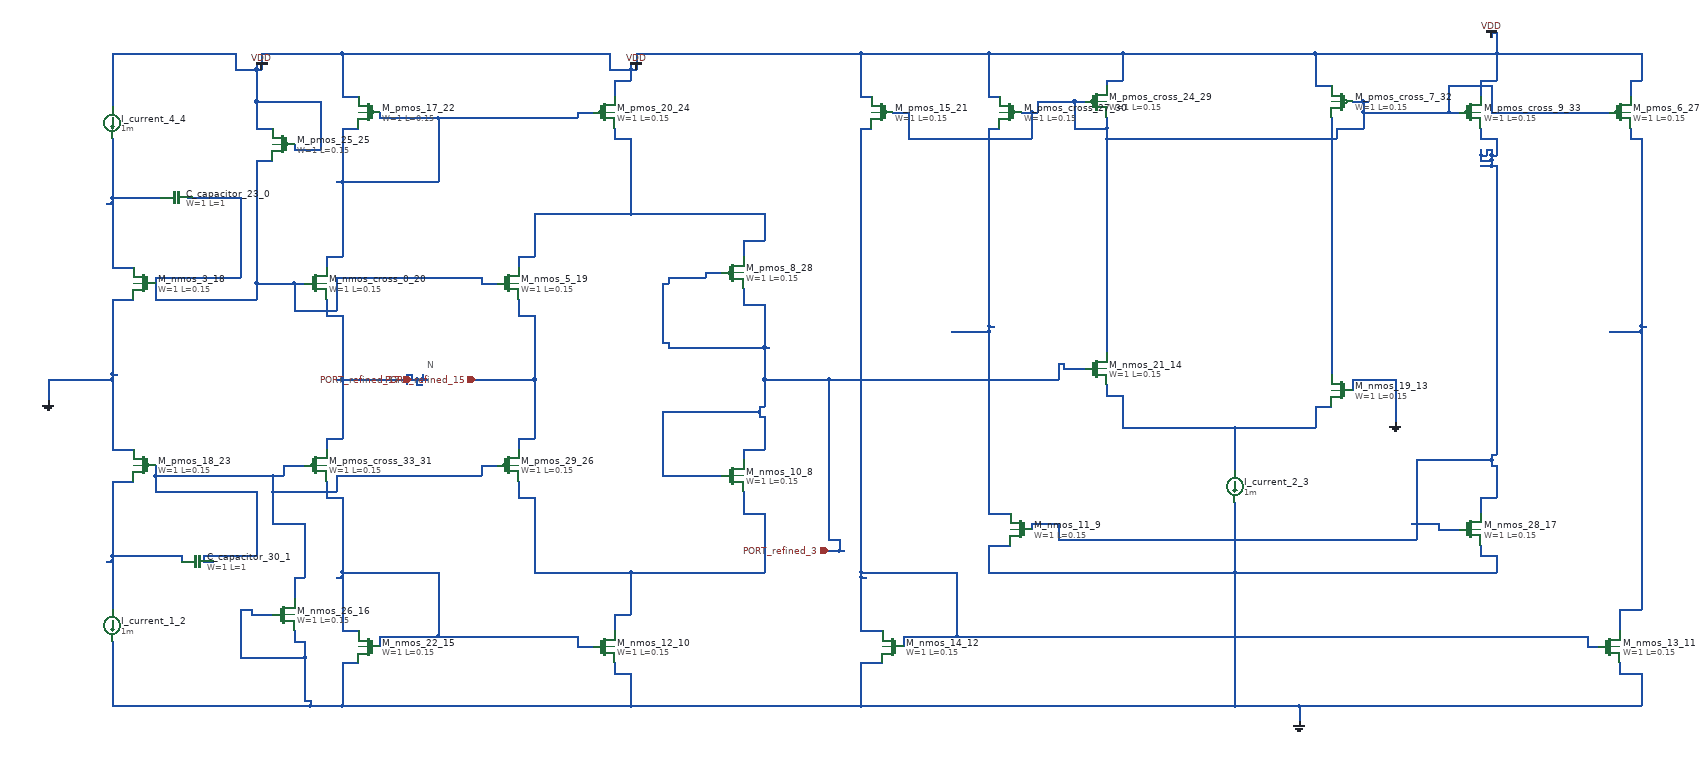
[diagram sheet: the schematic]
v {xschem version=3.4.8 file_version=1.2}
G {}
K {}
V {}
S {}
E {}
C {sky130_fd_pr/cap_mim_m3_1.sym} 320 440 1 0 {name="C_capacitor_23_0" model=cap_mim_m3_1 W=1 L=1 MF=1 spiceprefix=X}
C {sky130_fd_pr/cap_mim_m3_1.sym} 360 1120 1 0 {name="C_capacitor_30_1" model=cap_mim_m3_1 W=1 L=1 MF=1 spiceprefix=X}
C {devices/isource.sym} 200 1240 0 0 {name="I_current_1_2" value=1m}
C {devices/isource.sym} 2300 980 0 0 {name="I_current_2_3" value=1m}
C {devices/isource.sym} 200 300 0 0 {name="I_current_4_4" value=1m}
C {devices/gnd.sym} 2600 860 0 0 {name="l_gnd_16_5" lab="GND"}
C {devices/gnd.sym} 80 820 0 0 {name="l_gnd_31_6" lab="GND"}
C {devices/gnd.sym} 2420 1420 0 0 {name="l_gnd_37_7" lab="GND"}
C {sky130_fd_pr/nfet3_01v8.sym} 1360 960 0 0 {name="M_nmos_10_8"
W=1
L=0.15
body=GND
nf=1
mult=1
ad="expr('int((@nf + 1)/2) * @W / @nf * 0.29')"
pd="expr('2*int((@nf + 1)/2) * (@W / @nf + 0.29)')"
as="expr('int((@nf + 2)/2) * @W / @nf * 0.29')"
ps="expr('2*int((@nf + 2)/2) * (@W / @nf + 0.29)')"
nrd="expr('0.29 / @W ')" nrs="expr('0.29 / @W ')"
sa=0 sb=0 sd=0
model=nfet_01v8
spiceprefix=X
}
C {sky130_fd_pr/nfet3_01v8.sym} 1900 1060 0 1 {name="M_nmos_11_9"
W=1
L=0.15
body=GND
nf=1
mult=1
ad="expr('int((@nf + 1)/2) * @W / @nf * 0.29')"
pd="expr('2*int((@nf + 1)/2) * (@W / @nf + 0.29)')"
as="expr('int((@nf + 2)/2) * @W / @nf * 0.29')"
ps="expr('2*int((@nf + 2)/2) * (@W / @nf + 0.29)')"
nrd="expr('0.29 / @W ')" nrs="expr('0.29 / @W ')"
sa=0 sb=0 sd=0
model=nfet_01v8
spiceprefix=X
}
C {sky130_fd_pr/nfet3_01v8.sym} 1120 1280 0 0 {name="M_nmos_12_10"
W=1
L=0.15
body=GND
nf=1
mult=1
ad="expr('int((@nf + 1)/2) * @W / @nf * 0.29')"
pd="expr('2*int((@nf + 1)/2) * (@W / @nf + 0.29)')"
as="expr('int((@nf + 2)/2) * @W / @nf * 0.29')"
ps="expr('2*int((@nf + 2)/2) * (@W / @nf + 0.29)')"
nrd="expr('0.29 / @W ')" nrs="expr('0.29 / @W ')"
sa=0 sb=0 sd=0
model=nfet_01v8
spiceprefix=X
}
C {sky130_fd_pr/nfet3_01v8.sym} 3000 1280 0 0 {name="M_nmos_13_11"
W=1
L=0.15
body=GND
nf=1
mult=1
ad="expr('int((@nf + 1)/2) * @W / @nf * 0.29')"
pd="expr('2*int((@nf + 1)/2) * (@W / @nf + 0.29)')"
as="expr('int((@nf + 2)/2) * @W / @nf * 0.29')"
ps="expr('2*int((@nf + 2)/2) * (@W / @nf + 0.29)')"
nrd="expr('0.29 / @W ')" nrs="expr('0.29 / @W ')"
sa=0 sb=0 sd=0
model=nfet_01v8
spiceprefix=X
}
C {sky130_fd_pr/nfet3_01v8.sym} 1660 1280 0 1 {name="M_nmos_14_12"
W=1
L=0.15
body=GND
nf=1
mult=1
ad="expr('int((@nf + 1)/2) * @W / @nf * 0.29')"
pd="expr('2*int((@nf + 1)/2) * (@W / @nf + 0.29)')"
as="expr('int((@nf + 2)/2) * @W / @nf * 0.29')"
ps="expr('2*int((@nf + 2)/2) * (@W / @nf + 0.29)')"
nrd="expr('0.29 / @W ')" nrs="expr('0.29 / @W ')"
sa=0 sb=0 sd=0
model=nfet_01v8
spiceprefix=X
}
C {sky130_fd_pr/nfet3_01v8.sym} 2500 800 0 1 {name="M_nmos_19_13"
W=1
L=0.15
body=GND
nf=1
mult=1
ad="expr('int((@nf + 1)/2) * @W / @nf * 0.29')"
pd="expr('2*int((@nf + 1)/2) * (@W / @nf + 0.29)')"
as="expr('int((@nf + 2)/2) * @W / @nf * 0.29')"
ps="expr('2*int((@nf + 2)/2) * (@W / @nf + 0.29)')"
nrd="expr('0.29 / @W ')" nrs="expr('0.29 / @W ')"
sa=0 sb=0 sd=0
model=nfet_01v8
spiceprefix=X
}
C {sky130_fd_pr/nfet3_01v8.sym} 2040 760 0 0 {name="M_nmos_21_14"
W=1
L=0.15
body=GND
nf=1
mult=1
ad="expr('int((@nf + 1)/2) * @W / @nf * 0.29')"
pd="expr('2*int((@nf + 1)/2) * (@W / @nf + 0.29)')"
as="expr('int((@nf + 2)/2) * @W / @nf * 0.29')"
ps="expr('2*int((@nf + 2)/2) * (@W / @nf + 0.29)')"
nrd="expr('0.29 / @W ')" nrs="expr('0.29 / @W ')"
sa=0 sb=0 sd=0
model=nfet_01v8
spiceprefix=X
}
C {sky130_fd_pr/nfet3_01v8.sym} 680 1280 0 1 {name="M_nmos_22_15"
W=1
L=0.15
body=GND
nf=1
mult=1
ad="expr('int((@nf + 1)/2) * @W / @nf * 0.29')"
pd="expr('2*int((@nf + 1)/2) * (@W / @nf + 0.29)')"
as="expr('int((@nf + 2)/2) * @W / @nf * 0.29')"
ps="expr('2*int((@nf + 2)/2) * (@W / @nf + 0.29)')"
nrd="expr('0.29 / @W ')" nrs="expr('0.29 / @W ')"
sa=0 sb=0 sd=0
model=nfet_01v8
spiceprefix=X
}
C {sky130_fd_pr/nfet3_01v8.sym} 520 1220 0 0 {name="M_nmos_26_16"
W=1
L=0.15
body=GND
nf=1
mult=1
ad="expr('int((@nf + 1)/2) * @W / @nf * 0.29')"
pd="expr('2*int((@nf + 1)/2) * (@W / @nf + 0.29)')"
as="expr('int((@nf + 2)/2) * @W / @nf * 0.29')"
ps="expr('2*int((@nf + 2)/2) * (@W / @nf + 0.29)')"
nrd="expr('0.29 / @W ')" nrs="expr('0.29 / @W ')"
sa=0 sb=0 sd=0
model=nfet_01v8
spiceprefix=X
}
C {sky130_fd_pr/nfet3_01v8.sym} 2740 1060 0 0 {name="M_nmos_28_17"
W=1
L=0.15
body=GND
nf=1
mult=1
ad="expr('int((@nf + 1)/2) * @W / @nf * 0.29')"
pd="expr('2*int((@nf + 1)/2) * (@W / @nf + 0.29)')"
as="expr('int((@nf + 2)/2) * @W / @nf * 0.29')"
ps="expr('2*int((@nf + 2)/2) * (@W / @nf + 0.29)')"
nrd="expr('0.29 / @W ')" nrs="expr('0.29 / @W ')"
sa=0 sb=0 sd=0
model=nfet_01v8
spiceprefix=X
}
C {sky130_fd_pr/nfet3_01v8.sym} 260 600 0 1 {name="M_nmos_3_18"
W=1
L=0.15
body=GND
nf=1
mult=1
ad="expr('int((@nf + 1)/2) * @W / @nf * 0.29')"
pd="expr('2*int((@nf + 1)/2) * (@W / @nf + 0.29)')"
as="expr('int((@nf + 2)/2) * @W / @nf * 0.29')"
ps="expr('2*int((@nf + 2)/2) * (@W / @nf + 0.29)')"
nrd="expr('0.29 / @W ')" nrs="expr('0.29 / @W ')"
sa=0 sb=0 sd=0
model=nfet_01v8
spiceprefix=X
}
C {sky130_fd_pr/nfet3_01v8.sym} 940 600 0 0 {name="M_nmos_5_19"
W=1
L=0.15
body=GND
nf=1
mult=1
ad="expr('int((@nf + 1)/2) * @W / @nf * 0.29')"
pd="expr('2*int((@nf + 1)/2) * (@W / @nf + 0.29)')"
as="expr('int((@nf + 2)/2) * @W / @nf * 0.29')"
ps="expr('2*int((@nf + 2)/2) * (@W / @nf + 0.29)')"
nrd="expr('0.29 / @W ')" nrs="expr('0.29 / @W ')"
sa=0 sb=0 sd=0
model=nfet_01v8
spiceprefix=X
}
C {sky130_fd_pr/nfet3_01v8.sym} 580 600 0 0 {name="M_nmos_cross_0_20"
W=1
L=0.15
body=GND
nf=1
mult=1
ad="expr('int((@nf + 1)/2) * @W / @nf * 0.29')"
pd="expr('2*int((@nf + 1)/2) * (@W / @nf + 0.29)')"
as="expr('int((@nf + 2)/2) * @W / @nf * 0.29')"
ps="expr('2*int((@nf + 2)/2) * (@W / @nf + 0.29)')"
nrd="expr('0.29 / @W ')" nrs="expr('0.29 / @W ')"
sa=0 sb=0 sd=0
model=nfet_01v8
spiceprefix=X
}
C {sky130_fd_pr/pfet3_01v8.sym} 1640 280 0 1 {name="M_pmos_15_21"
W=1
L=0.15
body=VDD
nf=1
mult=1
ad="expr('int((@nf + 1)/2) * @W / @nf * 0.29')"
pd="expr('2*int((@nf + 1)/2) * (@W / @nf + 0.29)')"
as="expr('int((@nf + 2)/2) * @W / @nf * 0.29')"
ps="expr('2*int((@nf + 2)/2) * (@W / @nf + 0.29)')"
nrd="expr('0.29 / @W ')" nrs="expr('0.29 / @W ')"
sa=0 sb=0 sd=0
model=pfet_01v8
spiceprefix=X
}
C {sky130_fd_pr/pfet3_01v8.sym} 680 280 0 1 {name="M_pmos_17_22"
W=1
L=0.15
body=VDD
nf=1
mult=1
ad="expr('int((@nf + 1)/2) * @W / @nf * 0.29')"
pd="expr('2*int((@nf + 1)/2) * (@W / @nf + 0.29)')"
as="expr('int((@nf + 2)/2) * @W / @nf * 0.29')"
ps="expr('2*int((@nf + 2)/2) * (@W / @nf + 0.29)')"
nrd="expr('0.29 / @W ')" nrs="expr('0.29 / @W ')"
sa=0 sb=0 sd=0
model=pfet_01v8
spiceprefix=X
}
C {sky130_fd_pr/pfet3_01v8.sym} 260 940 0 1 {name="M_pmos_18_23"
W=1
L=0.15
body=VDD
nf=1
mult=1
ad="expr('int((@nf + 1)/2) * @W / @nf * 0.29')"
pd="expr('2*int((@nf + 1)/2) * (@W / @nf + 0.29)')"
as="expr('int((@nf + 2)/2) * @W / @nf * 0.29')"
ps="expr('2*int((@nf + 2)/2) * (@W / @nf + 0.29)')"
nrd="expr('0.29 / @W ')" nrs="expr('0.29 / @W ')"
sa=0 sb=0 sd=0
model=pfet_01v8
spiceprefix=X
}
C {sky130_fd_pr/pfet3_01v8.sym} 1120 280 0 0 {name="M_pmos_20_24"
W=1
L=0.15
body=VDD
nf=1
mult=1
ad="expr('int((@nf + 1)/2) * @W / @nf * 0.29')"
pd="expr('2*int((@nf + 1)/2) * (@W / @nf + 0.29)')"
as="expr('int((@nf + 2)/2) * @W / @nf * 0.29')"
ps="expr('2*int((@nf + 2)/2) * (@W / @nf + 0.29)')"
nrd="expr('0.29 / @W ')" nrs="expr('0.29 / @W ')"
sa=0 sb=0 sd=0
model=pfet_01v8
spiceprefix=X
}
C {sky130_fd_pr/pfet3_01v8.sym} 520 340 0 1 {name="M_pmos_25_25"
W=1
L=0.15
body=VDD
nf=1
mult=1
ad="expr('int((@nf + 1)/2) * @W / @nf * 0.29')"
pd="expr('2*int((@nf + 1)/2) * (@W / @nf + 0.29)')"
as="expr('int((@nf + 2)/2) * @W / @nf * 0.29')"
ps="expr('2*int((@nf + 2)/2) * (@W / @nf + 0.29)')"
nrd="expr('0.29 / @W ')" nrs="expr('0.29 / @W ')"
sa=0 sb=0 sd=0
model=pfet_01v8
spiceprefix=X
}
C {sky130_fd_pr/pfet3_01v8.sym} 940 940 0 0 {name="M_pmos_29_26"
W=1
L=0.15
body=VDD
nf=1
mult=1
ad="expr('int((@nf + 1)/2) * @W / @nf * 0.29')"
pd="expr('2*int((@nf + 1)/2) * (@W / @nf + 0.29)')"
as="expr('int((@nf + 2)/2) * @W / @nf * 0.29')"
ps="expr('2*int((@nf + 2)/2) * (@W / @nf + 0.29)')"
nrd="expr('0.29 / @W ')" nrs="expr('0.29 / @W ')"
sa=0 sb=0 sd=0
model=pfet_01v8
spiceprefix=X
}
C {sky130_fd_pr/pfet3_01v8.sym} 3020 280 0 0 {name="M_pmos_6_27"
W=1
L=0.15
body=VDD
nf=1
mult=1
ad="expr('int((@nf + 1)/2) * @W / @nf * 0.29')"
pd="expr('2*int((@nf + 1)/2) * (@W / @nf + 0.29)')"
as="expr('int((@nf + 2)/2) * @W / @nf * 0.29')"
ps="expr('2*int((@nf + 2)/2) * (@W / @nf + 0.29)')"
nrd="expr('0.29 / @W ')" nrs="expr('0.29 / @W ')"
sa=0 sb=0 sd=0
model=pfet_01v8
spiceprefix=X
}
C {sky130_fd_pr/pfet3_01v8.sym} 1360 580 0 0 {name="M_pmos_8_28"
W=1
L=0.15
body=VDD
nf=1
mult=1
ad="expr('int((@nf + 1)/2) * @W / @nf * 0.29')"
pd="expr('2*int((@nf + 1)/2) * (@W / @nf + 0.29)')"
as="expr('int((@nf + 2)/2) * @W / @nf * 0.29')"
ps="expr('2*int((@nf + 2)/2) * (@W / @nf + 0.29)')"
nrd="expr('0.29 / @W ')" nrs="expr('0.29 / @W ')"
sa=0 sb=0 sd=0
model=pfet_01v8
spiceprefix=X
}
C {sky130_fd_pr/pfet3_01v8.sym} 2040 260 0 0 {name="M_pmos_cross_24_29"
W=1
L=0.15
body=VDD
nf=1
mult=1
ad="expr('int((@nf + 1)/2) * @W / @nf * 0.29')"
pd="expr('2*int((@nf + 1)/2) * (@W / @nf + 0.29)')"
as="expr('int((@nf + 2)/2) * @W / @nf * 0.29')"
ps="expr('2*int((@nf + 2)/2) * (@W / @nf + 0.29)')"
nrd="expr('0.29 / @W ')" nrs="expr('0.29 / @W ')"
sa=0 sb=0 sd=0
model=pfet_01v8
spiceprefix=X
}
C {sky130_fd_pr/pfet3_01v8.sym} 1880 280 0 1 {name="M_pmos_cross_27_30"
W=1
L=0.15
body=VDD
nf=1
mult=1
ad="expr('int((@nf + 1)/2) * @W / @nf * 0.29')"
pd="expr('2*int((@nf + 1)/2) * (@W / @nf + 0.29)')"
as="expr('int((@nf + 2)/2) * @W / @nf * 0.29')"
ps="expr('2*int((@nf + 2)/2) * (@W / @nf + 0.29)')"
nrd="expr('0.29 / @W ')" nrs="expr('0.29 / @W ')"
sa=0 sb=0 sd=0
model=pfet_01v8
spiceprefix=X
}
C {sky130_fd_pr/pfet3_01v8.sym} 580 940 0 0 {name="M_pmos_cross_33_31"
W=1
L=0.15
body=VDD
nf=1
mult=1
ad="expr('int((@nf + 1)/2) * @W / @nf * 0.29')"
pd="expr('2*int((@nf + 1)/2) * (@W / @nf + 0.29)')"
as="expr('int((@nf + 2)/2) * @W / @nf * 0.29')"
ps="expr('2*int((@nf + 2)/2) * (@W / @nf + 0.29)')"
nrd="expr('0.29 / @W ')" nrs="expr('0.29 / @W ')"
sa=0 sb=0 sd=0
model=pfet_01v8
spiceprefix=X
}
C {sky130_fd_pr/pfet3_01v8.sym} 2500 260 0 1 {name="M_pmos_cross_7_32"
W=1
L=0.15
body=VDD
nf=1
mult=1
ad="expr('int((@nf + 1)/2) * @W / @nf * 0.29')"
pd="expr('2*int((@nf + 1)/2) * (@W / @nf + 0.29)')"
as="expr('int((@nf + 2)/2) * @W / @nf * 0.29')"
ps="expr('2*int((@nf + 2)/2) * (@W / @nf + 0.29)')"
nrd="expr('0.29 / @W ')" nrs="expr('0.29 / @W ')"
sa=0 sb=0 sd=0
model=pfet_01v8
spiceprefix=X
}
C {sky130_fd_pr/pfet3_01v8.sym} 2740 280 0 0 {name="M_pmos_cross_9_33"
W=1
L=0.15
body=VDD
nf=1
mult=1
ad="expr('int((@nf + 1)/2) * @W / @nf * 0.29')"
pd="expr('2*int((@nf + 1)/2) * (@W / @nf + 0.29)')"
as="expr('int((@nf + 2)/2) * @W / @nf * 0.29')"
ps="expr('2*int((@nf + 2)/2) * (@W / @nf + 0.29)')"
nrd="expr('0.29 / @W ')" nrs="expr('0.29 / @W ')"
sa=0 sb=0 sd=0
model=pfet_01v8
spiceprefix=X
}
C {devices/ipin.sym} 880 780 0 0 {name="p_port_35_34" lab="PORT_refined_15"}
C {devices/ipin.sym} 760 780 0 0 {name="p_port_38_35" lab="PORT_refined_17"}
T {N} 790 740 0 0 0.25 0.25 {}
C {devices/ipin.sym} 1540 1100 0 0 {name="p_port_99_36" lab="PORT_refined_3"}
C {devices/vdd.sym} 2780 140 0 0 {name="l_vdd_32_37" lab="VDD"}
C {devices/vdd.sym} 480 200 0 0 {name="l_vdd_34_38" lab="VDD"}
C {devices/vdd.sym} 1180 200 0 0 {name="l_vdd_36_39" lab="VDD"}
N 200 570 240 570 {}
N 190 450 200 450 {}
N 200 440 290 440 {}
N 290 440 300 440 {}
N 200 570 200 450 {}
N 200 450 200 440 {}
N 200 440 200 330 {}
N 540 650 620 650 {}
N 280 630 470 630 {}
N 470 600 540 600 {}
N 540 600 560 600 {}
N 890 600 920 600 {}
N 280 590 440 590 {}
N 620 590 890 590 {}
N 340 440 350 440 {}
N 350 440 440 440 {}
N 470 370 500 370 {}
N 280 630 280 600 {}
N 280 600 280 590 {}
N 440 590 440 440 {}
N 470 630 470 600 {}
N 470 600 470 370 {}
N 540 650 540 600 {}
N 620 650 620 590 {}
N 890 600 890 590 {}
N 2960 1280 2980 1280 {}
N 1680 1260 1780 1260 {}
N 1780 1260 2960 1260 {}
N 1600 1250 1640 1250 {}
N 1600 1150 1610 1150 {}
N 1600 1140 1780 1140 {}
N 1600 310 1620 310 {}
N 1600 1250 1600 1150 {}
N 1600 1150 1600 1140 {}
N 1600 1140 1600 310 {}
N 1680 1280 1680 1260 {}
N 1780 1260 1780 1140 {}
N 2960 1280 2960 1260 {}
N 2090 870 2300 870 {}
N 2300 870 2450 870 {}
N 2450 830 2480 830 {}
N 2060 810 2090 810 {}
N 2060 810 2060 790 {}
N 2090 870 2090 810 {}
N 2300 950 2300 870 {}
N 2450 870 2450 830 {}
N 1690 330 1920 330 {}
N 2060 330 2490 330 {}
N 2000 310 2060 310 {}
N 2490 310 2540 310 {}
N 1660 280 1690 280 {}
N 1900 280 1920 280 {}
N 1920 280 1930 280 {}
N 2540 280 2700 280 {}
N 2700 280 2720 280 {}
N 2780 280 3000 280 {}
N 1930 260 2000 260 {}
N 2000 260 2020 260 {}
N 2520 260 2540 260 {}
N 2540 260 2550 260 {}
N 2700 230 2780 230 {}
N 1690 330 1690 280 {}
N 1920 330 1920 280 {}
N 1930 280 1930 260 {}
N 2000 310 2000 260 {}
N 2060 730 2060 330 {}
N 2060 330 2060 310 {}
N 2060 310 2060 290 {}
N 2490 330 2490 310 {}
N 2540 310 2540 280 {}
N 2540 280 2540 260 {}
N 2700 280 2700 230 {}
N 2780 280 2780 230 {}
N 540 1150 560 1150 {}
N 370 1120 390 1120 {}
N 370 1110 470 1110 {}
N 500 1050 560 1050 {}
N 280 990 470 990 {}
N 500 990 620 990 {}
N 280 960 500 960 {}
N 500 960 520 960 {}
N 620 960 890 960 {}
N 520 940 560 940 {}
N 890 940 920 940 {}
N 280 990 280 960 {}
N 280 960 280 940 {}
N 370 1120 370 1110 {}
N 470 1110 470 990 {}
N 500 1050 500 990 {}
N 500 990 500 960 {}
N 520 960 520 940 {}
N 540 1190 540 1150 {}
N 560 1150 560 1050 {}
N 620 990 620 960 {}
N 890 960 890 940 {}
N 960 550 990 550 {}
N 1380 520 1420 520 {}
N 990 470 1170 470 {}
N 1170 470 1420 470 {}
N 1140 330 1170 330 {}
N 960 570 960 550 {}
N 990 550 990 470 {}
N 1140 330 1140 310 {}
N 1170 470 1170 330 {}
N 1380 550 1380 520 {}
N 1420 520 1420 470 {}
N 960 890 990 890 {}
N 870 780 880 780 {}
N 880 780 990 780 {}
N 960 660 990 660 {}
N 960 910 960 890 {}
N 960 660 960 630 {}
N 990 890 990 780 {}
N 990 780 990 660 {}
N 600 550 630 550 {}
N 620 410 630 410 {}
N 630 410 810 410 {}
N 630 310 660 310 {}
N 700 290 810 290 {}
N 810 290 1070 290 {}
N 1070 280 1100 280 {}
N 600 570 600 550 {}
N 630 550 630 410 {}
N 630 410 630 310 {}
N 700 290 700 280 {}
N 810 410 810 290 {}
N 1070 290 1070 280 {}
N 600 890 630 890 {}
N 770 790 780 790 {}
N 620 780 630 780 {}
N 630 780 750 780 {}
N 760 780 770 780 {}
N 770 780 780 780 {}
N 780 780 790 780 {}
N 750 770 760 770 {}
N 600 660 630 660 {}
N 600 910 600 890 {}
N 600 660 600 630 {}
N 630 890 630 780 {}
N 630 780 630 660 {}
N 750 790 750 780 {}
N 750 780 750 770 {}
N 760 780 760 770 {}
N 770 790 770 780 {}
N 780 780 780 770 {}
N 540 350 590 350 {}
N 470 310 500 310 {}
N 470 260 590 260 {}
N 630 250 660 250 {}
N 1600 250 1620 250 {}
N 1840 250 1860 250 {}
N 2450 230 2480 230 {}
N 1140 220 1170 220 {}
N 2060 220 2090 220 {}
N 2760 220 2790 220 {}
N 3040 220 3060 220 {}
N 430 200 470 200 {}
N 470 200 480 200 {}
N 1130 200 1170 200 {}
N 1170 200 1180 200 {}
N 200 170 430 170 {}
N 480 170 630 170 {}
N 630 170 1130 170 {}
N 1180 170 1600 170 {}
N 1600 170 1840 170 {}
N 1840 170 2090 170 {}
N 2090 170 2450 170 {}
N 2450 170 2790 170 {}
N 2790 170 3060 170 {}
N 2780 130 2790 130 {}
N 200 270 200 170 {}
N 430 200 430 170 {}
N 470 310 470 260 {}
N 470 260 470 200 {}
N 470 200 470 190 {}
N 480 200 480 170 {}
N 540 350 540 340 {}
N 590 350 590 260 {}
N 630 250 630 170 {}
N 1130 200 1130 170 {}
N 1140 250 1140 220 {}
N 1170 220 1170 200 {}
N 1170 200 1170 190 {}
N 1180 200 1180 170 {}
N 1600 250 1600 170 {}
N 1840 250 1840 170 {}
N 2060 230 2060 220 {}
N 2090 220 2090 170 {}
N 2450 230 2450 170 {}
N 2760 250 2760 220 {}
N 2780 140 2780 130 {}
N 2790 220 2790 170 {}
N 2790 170 2790 130 {}
N 3040 250 3040 220 {}
N 3060 220 3060 170 {}
N 2480 770 2480 290 {}
N 200 1390 570 1390 {}
N 570 1390 630 1390 {}
N 630 1390 1170 1390 {}
N 1170 1390 1600 1390 {}
N 1600 1390 2300 1390 {}
N 2300 1390 2420 1390 {}
N 2420 1390 3060 1390 {}
N 560 1380 570 1380 {}
N 1140 1330 1170 1330 {}
N 3020 1330 3060 1330 {}
N 630 1310 660 1310 {}
N 1600 1310 1640 1310 {}
N 440 1300 560 1300 {}
N 540 1270 560 1270 {}
N 460 1220 500 1220 {}
N 440 1210 460 1210 {}
N 1840 1140 2300 1140 {}
N 2300 1140 2790 1140 {}
N 2760 1110 2790 1110 {}
N 1840 1090 1880 1090 {}
N 200 910 240 910 {}
N 80 780 200 780 {}
N 2520 780 2600 780 {}
N 200 770 210 770 {}
N 200 630 240 630 {}
N 80 820 80 780 {}
N 200 1390 200 1270 {}
N 200 910 200 780 {}
N 200 780 200 770 {}
N 200 770 200 630 {}
N 440 1300 440 1210 {}
N 460 1220 460 1210 {}
N 540 1270 540 1250 {}
N 560 1380 560 1300 {}
N 560 1300 560 1270 {}
N 570 1390 570 1380 {}
N 630 1390 630 1310 {}
N 1140 1330 1140 1310 {}
N 1170 1390 1170 1330 {}
N 1600 1390 1600 1310 {}
N 1840 1140 1840 1090 {}
N 2300 1390 2300 1140 {}
N 2300 1140 2300 1010 {}
N 2420 1420 2420 1390 {}
N 2520 800 2520 780 {}
N 2600 860 2600 780 {}
N 2760 1110 2760 1090 {}
N 2790 1140 2790 1110 {}
N 3020 1330 3020 1310 {}
N 3060 1390 3060 1330 {}
N 1540 1100 1560 1100 {}
N 1560 1100 1570 1100 {}
N 1540 1080 1560 1080 {}
N 1230 960 1340 960 {}
N 1380 910 1420 910 {}
N 1410 850 1420 850 {}
N 1230 840 1410 840 {}
N 1410 830 1420 830 {}
N 1420 780 1540 780 {}
N 1540 780 1970 780 {}
N 1980 760 2020 760 {}
N 1970 750 1980 750 {}
N 1240 720 1420 720 {}
N 1420 720 1430 720 {}
N 1230 710 1240 710 {}
N 1380 640 1420 640 {}
N 1230 600 1240 600 {}
N 1240 590 1310 590 {}
N 1310 580 1340 580 {}
N 1230 960 1230 840 {}
N 1230 710 1230 600 {}
N 1240 720 1240 710 {}
N 1240 600 1240 590 {}
N 1310 590 1310 580 {}
N 1380 930 1380 910 {}
N 1380 640 1380 610 {}
N 1410 850 1410 840 {}
N 1410 840 1410 830 {}
N 1420 910 1420 850 {}
N 1420 830 1420 780 {}
N 1420 780 1420 720 {}
N 1420 720 1420 640 {}
N 1540 1080 1540 780 {}
N 1560 1100 1560 1080 {}
N 1970 780 1970 750 {}
N 1980 760 1980 750 {}
N 1140 1220 1170 1220 {}
N 990 1140 1170 1140 {}
N 1170 1140 1420 1140 {}
N 1380 1030 1420 1030 {}
N 960 1000 990 1000 {}
N 960 1000 960 970 {}
N 990 1140 990 1000 {}
N 1140 1250 1140 1220 {}
N 1170 1220 1170 1140 {}
N 1380 1030 1380 990 {}
N 1420 1140 1420 1030 {}
N 1840 1030 1880 1030 {}
N 1770 690 1840 690 {}
N 1840 680 1850 680 {}
N 1840 310 1860 310 {}
N 1840 1030 1840 690 {}
N 1840 690 1840 680 {}
N 1840 680 1840 310 {}
N 1970 1080 2640 1080 {}
N 2680 1060 2720 1060 {}
N 1920 1050 1970 1050 {}
N 2630 1050 2640 1050 {}
N 2640 1050 2680 1050 {}
N 2760 1000 2790 1000 {}
N 2780 940 2790 940 {}
N 2640 930 2780 930 {}
N 2780 920 2790 920 {}
N 2760 380 2780 380 {}
N 2780 380 2790 380 {}
N 2760 370 2780 370 {}
N 2760 360 2770 360 {}
N 2780 360 2790 360 {}
N 2770 350 2780 350 {}
N 2760 330 2790 330 {}
N 1920 1060 1920 1050 {}
N 1970 1080 1970 1050 {}
N 2640 1080 2640 1050 {}
N 2640 1050 2640 930 {}
N 2680 1060 2680 1050 {}
N 2760 1030 2760 1000 {}
N 2760 370 2760 360 {}
N 2760 360 2760 350 {}
N 2760 330 2760 310 {}
N 2770 360 2770 350 {}
N 2780 940 2780 930 {}
N 2780 930 2780 920 {}
N 2780 380 2780 370 {}
N 2780 370 2780 360 {}
N 2780 360 2780 350 {}
N 2790 1000 2790 940 {}
N 2790 920 2790 380 {}
N 2790 360 2790 330 {}
N 190 1120 200 1120 {}
N 200 1110 330 1110 {}
N 200 970 240 970 {}
N 200 1210 200 1120 {}
N 200 1120 200 1110 {}
N 200 1110 200 970 {}
N 330 1120 330 1110 {}
N 1070 1280 1100 1280 {}
N 700 1260 810 1260 {}
N 810 1260 1070 1260 {}
N 630 1250 660 1250 {}
N 620 1150 630 1150 {}
N 630 1140 810 1140 {}
N 600 1000 630 1000 {}
N 600 1000 600 970 {}
N 630 1250 630 1150 {}
N 630 1150 630 1140 {}
N 630 1140 630 1000 {}
N 700 1280 700 1260 {}
N 810 1260 810 1140 {}
N 1070 1280 1070 1260 {}
N 3020 1210 3060 1210 {}
N 3000 690 3060 690 {}
N 3060 680 3070 680 {}
N 3040 330 3060 330 {}
N 3020 1250 3020 1210 {}
N 3040 330 3040 310 {}
N 3060 1210 3060 690 {}
N 3060 690 3060 680 {}
N 3060 680 3060 330 {}
